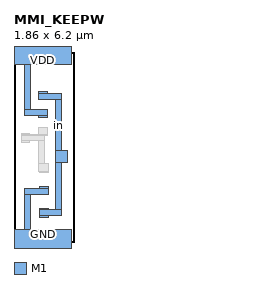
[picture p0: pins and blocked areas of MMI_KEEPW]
MACRO MMI_KEEPW
	CLASS CORE ;
	FOREIGN MMI_KEEPW 0 0 ;
	SIZE 1.86 BY 6.2 ;
	SYMMETRY X Y ;
	SITE CORE1 ;
	PIN GND
		DIRECTION inout ;
		USE GROUND ;
		PORT
			LAYER M1 ;
			RECT 0.83 1.73 1.11 1.82 ;
			LAYER M1 ;
			RECT 0.33 1.54 1.11 1.73 ;
			LAYER M1 ;
			RECT 0.33 0.42 0.525 1.54 ;
			LAYER M1 ;
			RECT 0 -0.42 1.86 0.42 ;
		END
	END GND
	PIN VDD
		DIRECTION inout ;
		USE POWER ;
		PORT
			LAYER M1 ;
			RECT 0 5.78 1.86 6.62 ;
			LAYER M1 ;
			RECT 0.355 4.33 0.55 5.78 ;
			LAYER M1 ;
			RECT 0.355 4.14 1.08 4.33 ;
			LAYER M1 ;
			RECT 0.8 4.05 1.08 4.14 ;
		END
	END VDD
	PIN in
		DIRECTION inout ;
		USE SIGNAL ;
		PORT
			LAYER M1 ;
			RECT 0.8 4.83 1.08 4.92 ;
			LAYER M1 ;
			RECT 0.8 4.64 1.555 4.83 ;
			LAYER M1 ;
			RECT 1.36 2.98 1.555 4.64 ;
			LAYER M1 ;
			RECT 1.36 2.6 1.74 2.98 ;
			LAYER M1 ;
			RECT 0.83 1.065 1.11 1.08 ;
			LAYER M1 ;
			RECT 1.36 1.065 1.555 2.6 ;
			LAYER M1 ;
			RECT 0.83 0.87 1.555 1.065 ;
			LAYER M1 ;
			RECT 0.83 0.8 1.11 0.87 ;
		END
		AntennaGateArea 0.1575 ;
		AntennaDiffArea 0.2765 ;
	END in
	OBS
		LAYER M1 ;
		RECT 0.23 3.5 0.51 3.535 ;
		LAYER M1 ;
		RECT 0.8 3.5 1.08 3.74 ;
		LAYER M1 ;
		RECT 0.23 3.46 1.08 3.5 ;
		LAYER M1 ;
		RECT 0.23 3.305 1 3.46 ;
		LAYER M1 ;
		RECT 0.23 3.255 0.51 3.305 ;
		LAYER M1 ;
		RECT 0.81 2.56 1 3.305 ;
		LAYER M1 ;
		RECT 0.81 2.285 1.11 2.56 ;
		LAYER M1 ;
		RECT 0.83 2.28 1.11 2.285 ;
	END
END MMI_KEEPW
